VERSION 5.7 ;
  NOWIREEXTENSIONATPIN ON ;
  DIVIDERCHAR "/" ;
  BUSBITCHARS "[]" ;
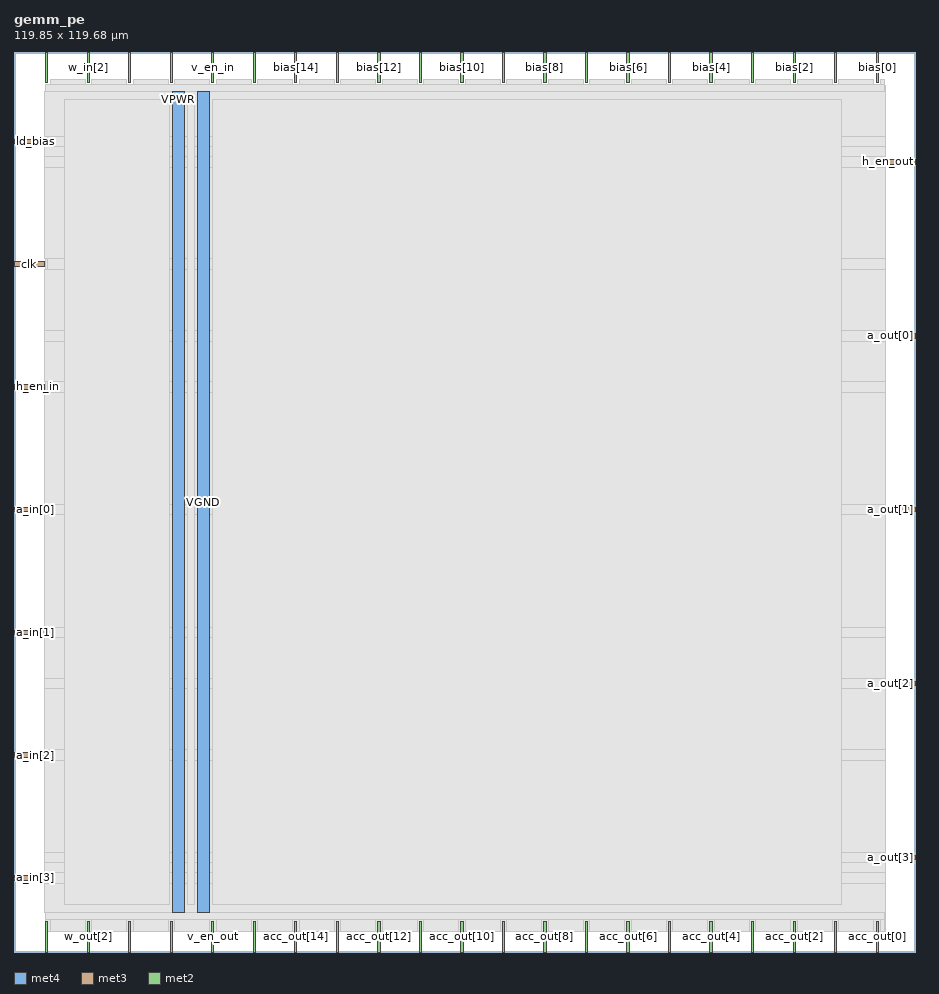
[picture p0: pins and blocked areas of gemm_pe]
MACRO gemm_pe
  CLASS BLOCK ;
  FOREIGN gemm_pe ;
  ORIGIN 0.000 0.000 ;
  SIZE 119.850 BY 119.680 ;
  PIN VGND
    DIRECTION INOUT ;
    USE GROUND ;
    PORT
      LAYER met4 ;
        RECT 24.340 5.200 25.940 114.480 ;
    END
  END VGND
  PIN VPWR
    DIRECTION INOUT ;
    USE POWER ;
    PORT
      LAYER met4 ;
        RECT 21.040 5.200 22.640 114.480 ;
    END
  END VPWR
  PIN a_in[0]
    DIRECTION INPUT ;
    USE SIGNAL ;
    ANTENNAGATEAREA 0.990000 ;
    PORT
      LAYER met3 ;
        RECT 0.000 58.520 4.000 59.120 ;
    END
  END a_in[0]
  PIN a_in[1]
    DIRECTION INPUT ;
    USE SIGNAL ;
    ANTENNAGATEAREA 1.237500 ;
    PORT
      LAYER met3 ;
        RECT 0.000 42.200 4.000 42.800 ;
    END
  END a_in[1]
  PIN a_in[2]
    DIRECTION INPUT ;
    USE SIGNAL ;
    ANTENNAGATEAREA 1.485000 ;
    PORT
      LAYER met3 ;
        RECT 0.000 25.880 4.000 26.480 ;
    END
  END a_in[2]
  PIN a_in[3]
    DIRECTION INPUT ;
    USE SIGNAL ;
    ANTENNAGATEAREA 1.116000 ;
    PORT
      LAYER met3 ;
        RECT 0.000 9.560 4.000 10.160 ;
    END
  END a_in[3]
  PIN a_out[0]
    DIRECTION OUTPUT ;
    USE SIGNAL ;
    ANTENNADIFFAREA 0.445500 ;
    PORT
      LAYER met3 ;
        RECT 115.850 81.640 119.850 82.240 ;
    END
  END a_out[0]
  PIN a_out[1]
    DIRECTION OUTPUT ;
    USE SIGNAL ;
    ANTENNADIFFAREA 0.445500 ;
    PORT
      LAYER met3 ;
        RECT 115.850 58.520 119.850 59.120 ;
    END
  END a_out[1]
  PIN a_out[2]
    DIRECTION OUTPUT ;
    USE SIGNAL ;
    ANTENNADIFFAREA 0.445500 ;
    PORT
      LAYER met3 ;
        RECT 115.850 35.400 119.850 36.000 ;
    END
  END a_out[2]
  PIN a_out[3]
    DIRECTION OUTPUT ;
    USE SIGNAL ;
    ANTENNADIFFAREA 0.445500 ;
    PORT
      LAYER met3 ;
        RECT 115.850 12.280 119.850 12.880 ;
    END
  END a_out[3]
  PIN acc_out[0]
    DIRECTION OUTPUT ;
    USE SIGNAL ;
    ANTENNAGATEAREA 2.475000 ;
    ANTENNADIFFAREA 0.445500 ;
    PORT
      LAYER met2 ;
        RECT 114.630 0.000 114.910 4.000 ;
    END
  END acc_out[0]
  PIN acc_out[10]
    DIRECTION OUTPUT ;
    USE SIGNAL ;
    ANTENNAGATEAREA 2.227500 ;
    ANTENNADIFFAREA 0.445500 ;
    PORT
      LAYER met2 ;
        RECT 59.430 0.000 59.710 4.000 ;
    END
  END acc_out[10]
  PIN acc_out[11]
    DIRECTION OUTPUT ;
    USE SIGNAL ;
    ANTENNAGATEAREA 2.722500 ;
    ANTENNADIFFAREA 0.445500 ;
    PORT
      LAYER met2 ;
        RECT 53.910 0.000 54.190 4.000 ;
    END
  END acc_out[11]
  PIN acc_out[12]
    DIRECTION OUTPUT ;
    USE SIGNAL ;
    ANTENNAGATEAREA 2.227500 ;
    ANTENNADIFFAREA 0.445500 ;
    PORT
      LAYER met2 ;
        RECT 48.390 0.000 48.670 4.000 ;
    END
  END acc_out[12]
  PIN acc_out[13]
    DIRECTION OUTPUT ;
    USE SIGNAL ;
    ANTENNAGATEAREA 2.227500 ;
    ANTENNADIFFAREA 0.445500 ;
    PORT
      LAYER met2 ;
        RECT 42.870 0.000 43.150 4.000 ;
    END
  END acc_out[13]
  PIN acc_out[14]
    DIRECTION OUTPUT ;
    USE SIGNAL ;
    ANTENNAGATEAREA 4.207500 ;
    ANTENNADIFFAREA 0.445500 ;
    PORT
      LAYER met2 ;
        RECT 37.350 0.000 37.630 4.000 ;
    END
  END acc_out[14]
  PIN acc_out[15]
    DIRECTION OUTPUT ;
    USE SIGNAL ;
    ANTENNADIFFAREA 0.445500 ;
    PORT
      LAYER met2 ;
        RECT 31.830 0.000 32.110 4.000 ;
    END
  END acc_out[15]
  PIN acc_out[1]
    DIRECTION OUTPUT ;
    USE SIGNAL ;
    ANTENNAGATEAREA 1.980000 ;
    ANTENNADIFFAREA 0.445500 ;
    PORT
      LAYER met2 ;
        RECT 109.110 0.000 109.390 4.000 ;
    END
  END acc_out[1]
  PIN acc_out[2]
    DIRECTION OUTPUT ;
    USE SIGNAL ;
    ANTENNAGATEAREA 1.485000 ;
    ANTENNADIFFAREA 0.445500 ;
    PORT
      LAYER met2 ;
        RECT 103.590 0.000 103.870 4.000 ;
    END
  END acc_out[2]
  PIN acc_out[3]
    DIRECTION OUTPUT ;
    USE SIGNAL ;
    ANTENNAGATEAREA 1.485000 ;
    ANTENNADIFFAREA 0.445500 ;
    PORT
      LAYER met2 ;
        RECT 98.070 0.000 98.350 4.000 ;
    END
  END acc_out[3]
  PIN acc_out[4]
    DIRECTION OUTPUT ;
    USE SIGNAL ;
    ANTENNAGATEAREA 1.980000 ;
    ANTENNADIFFAREA 0.445500 ;
    PORT
      LAYER met2 ;
        RECT 92.550 0.000 92.830 4.000 ;
    END
  END acc_out[4]
  PIN acc_out[5]
    DIRECTION OUTPUT ;
    USE SIGNAL ;
    ANTENNAGATEAREA 1.485000 ;
    ANTENNADIFFAREA 0.445500 ;
    PORT
      LAYER met2 ;
        RECT 87.030 0.000 87.310 4.000 ;
    END
  END acc_out[5]
  PIN acc_out[6]
    DIRECTION OUTPUT ;
    USE SIGNAL ;
    ANTENNAGATEAREA 1.485000 ;
    ANTENNADIFFAREA 0.445500 ;
    PORT
      LAYER met2 ;
        RECT 81.510 0.000 81.790 4.000 ;
    END
  END acc_out[6]
  PIN acc_out[7]
    DIRECTION OUTPUT ;
    USE SIGNAL ;
    ANTENNAGATEAREA 2.050500 ;
    ANTENNADIFFAREA 0.445500 ;
    PORT
      LAYER met2 ;
        RECT 75.990 0.000 76.270 4.000 ;
    END
  END acc_out[7]
  PIN acc_out[8]
    DIRECTION OUTPUT ;
    USE SIGNAL ;
    ANTENNAGATEAREA 1.681500 ;
    ANTENNADIFFAREA 0.445500 ;
    PORT
      LAYER met2 ;
        RECT 70.470 0.000 70.750 4.000 ;
    END
  END acc_out[8]
  PIN acc_out[9]
    DIRECTION OUTPUT ;
    USE SIGNAL ;
    ANTENNAGATEAREA 1.929000 ;
    ANTENNADIFFAREA 0.445500 ;
    PORT
      LAYER met2 ;
        RECT 64.950 0.000 65.230 4.000 ;
    END
  END acc_out[9]
  PIN bias[0]
    DIRECTION INPUT ;
    USE SIGNAL ;
    ANTENNAGATEAREA 0.159000 ;
    PORT
      LAYER met2 ;
        RECT 114.630 115.680 114.910 119.680 ;
    END
  END bias[0]
  PIN bias[10]
    DIRECTION INPUT ;
    USE SIGNAL ;
    ANTENNAGATEAREA 0.247500 ;
    PORT
      LAYER met2 ;
        RECT 59.430 115.680 59.710 119.680 ;
    END
  END bias[10]
  PIN bias[11]
    DIRECTION INPUT ;
    USE SIGNAL ;
    ANTENNAGATEAREA 0.247500 ;
    PORT
      LAYER met2 ;
        RECT 53.910 115.680 54.190 119.680 ;
    END
  END bias[11]
  PIN bias[12]
    DIRECTION INPUT ;
    USE SIGNAL ;
    ANTENNAGATEAREA 0.159000 ;
    PORT
      LAYER met2 ;
        RECT 48.390 115.680 48.670 119.680 ;
    END
  END bias[12]
  PIN bias[13]
    DIRECTION INPUT ;
    USE SIGNAL ;
    ANTENNAGATEAREA 0.159000 ;
    PORT
      LAYER met2 ;
        RECT 42.870 115.680 43.150 119.680 ;
    END
  END bias[13]
  PIN bias[14]
    DIRECTION INPUT ;
    USE SIGNAL ;
    ANTENNAGATEAREA 0.247500 ;
    PORT
      LAYER met2 ;
        RECT 37.350 115.680 37.630 119.680 ;
    END
  END bias[14]
  PIN bias[15]
    DIRECTION INPUT ;
    USE SIGNAL ;
    ANTENNAGATEAREA 0.495000 ;
    PORT
      LAYER met2 ;
        RECT 31.830 115.680 32.110 119.680 ;
    END
  END bias[15]
  PIN bias[1]
    DIRECTION INPUT ;
    USE SIGNAL ;
    ANTENNAGATEAREA 0.159000 ;
    PORT
      LAYER met2 ;
        RECT 109.110 115.680 109.390 119.680 ;
    END
  END bias[1]
  PIN bias[2]
    DIRECTION INPUT ;
    USE SIGNAL ;
    ANTENNAGATEAREA 0.159000 ;
    PORT
      LAYER met2 ;
        RECT 103.590 115.680 103.870 119.680 ;
    END
  END bias[2]
  PIN bias[3]
    DIRECTION INPUT ;
    USE SIGNAL ;
    ANTENNAGATEAREA 0.159000 ;
    PORT
      LAYER met2 ;
        RECT 98.070 115.680 98.350 119.680 ;
    END
  END bias[3]
  PIN bias[4]
    DIRECTION INPUT ;
    USE SIGNAL ;
    ANTENNAGATEAREA 0.159000 ;
    PORT
      LAYER met2 ;
        RECT 92.550 115.680 92.830 119.680 ;
    END
  END bias[4]
  PIN bias[5]
    DIRECTION INPUT ;
    USE SIGNAL ;
    ANTENNAGATEAREA 0.159000 ;
    PORT
      LAYER met2 ;
        RECT 87.030 115.680 87.310 119.680 ;
    END
  END bias[5]
  PIN bias[6]
    DIRECTION INPUT ;
    USE SIGNAL ;
    ANTENNAGATEAREA 0.593700 ;
    ANTENNADIFFAREA 0.434700 ;
    PORT
      LAYER met2 ;
        RECT 81.510 115.680 81.790 119.680 ;
    END
  END bias[6]
  PIN bias[7]
    DIRECTION INPUT ;
    USE SIGNAL ;
    ANTENNAGATEAREA 0.593700 ;
    ANTENNADIFFAREA 0.434700 ;
    PORT
      LAYER met2 ;
        RECT 75.990 115.680 76.270 119.680 ;
    END
  END bias[7]
  PIN bias[8]
    DIRECTION INPUT ;
    USE SIGNAL ;
    ANTENNAGATEAREA 0.593700 ;
    ANTENNADIFFAREA 0.434700 ;
    PORT
      LAYER met2 ;
        RECT 70.470 115.680 70.750 119.680 ;
    END
  END bias[8]
  PIN bias[9]
    DIRECTION INPUT ;
    USE SIGNAL ;
    ANTENNAGATEAREA 0.593700 ;
    ANTENNADIFFAREA 0.434700 ;
    PORT
      LAYER met2 ;
        RECT 64.950 115.680 65.230 119.680 ;
    END
  END bias[9]
  PIN clk
    DIRECTION INPUT ;
    USE SIGNAL ;
    ANTENNAGATEAREA 0.852000 ;
    PORT
      LAYER met3 ;
        RECT 0.000 91.160 4.000 91.760 ;
    END
  END clk
  PIN h_en_in
    DIRECTION INPUT ;
    USE SIGNAL ;
    ANTENNAGATEAREA 2.601000 ;
    PORT
      LAYER met3 ;
        RECT 0.000 74.840 4.000 75.440 ;
    END
  END h_en_in
  PIN h_en_out
    DIRECTION OUTPUT ;
    USE SIGNAL ;
    ANTENNADIFFAREA 0.445500 ;
    PORT
      LAYER met3 ;
        RECT 115.850 104.760 119.850 105.360 ;
    END
  END h_en_out
  PIN ld_bias
    DIRECTION INPUT ;
    USE SIGNAL ;
    ANTENNAGATEAREA 4.383000 ;
    PORT
      LAYER met3 ;
        RECT 0.000 107.480 4.000 108.080 ;
    END
  END ld_bias
  PIN v_en_in
    DIRECTION INPUT ;
    USE SIGNAL ;
    ANTENNAGATEAREA 2.601000 ;
    PORT
      LAYER met2 ;
        RECT 26.310 115.680 26.590 119.680 ;
    END
  END v_en_in
  PIN v_en_out
    DIRECTION OUTPUT ;
    USE SIGNAL ;
    ANTENNADIFFAREA 0.445500 ;
    PORT
      LAYER met2 ;
        RECT 26.310 0.000 26.590 4.000 ;
    END
  END v_en_out
  PIN w_in[0]
    DIRECTION INPUT ;
    USE SIGNAL ;
    ANTENNAGATEAREA 0.990000 ;
    PORT
      LAYER met2 ;
        RECT 20.790 115.680 21.070 119.680 ;
    END
  END w_in[0]
  PIN w_in[1]
    DIRECTION INPUT ;
    USE SIGNAL ;
    ANTENNAGATEAREA 1.237500 ;
    PORT
      LAYER met2 ;
        RECT 15.270 115.680 15.550 119.680 ;
    END
  END w_in[1]
  PIN w_in[2]
    DIRECTION INPUT ;
    USE SIGNAL ;
    ANTENNAGATEAREA 1.485000 ;
    PORT
      LAYER met2 ;
        RECT 9.750 115.680 10.030 119.680 ;
    END
  END w_in[2]
  PIN w_in[3]
    DIRECTION INPUT ;
    USE SIGNAL ;
    ANTENNAGATEAREA 1.116000 ;
    PORT
      LAYER met2 ;
        RECT 4.230 115.680 4.510 119.680 ;
    END
  END w_in[3]
  PIN w_out[0]
    DIRECTION OUTPUT ;
    USE SIGNAL ;
    ANTENNADIFFAREA 0.445500 ;
    PORT
      LAYER met2 ;
        RECT 20.790 0.000 21.070 4.000 ;
    END
  END w_out[0]
  PIN w_out[1]
    DIRECTION OUTPUT ;
    USE SIGNAL ;
    ANTENNADIFFAREA 0.445500 ;
    PORT
      LAYER met2 ;
        RECT 15.270 0.000 15.550 4.000 ;
    END
  END w_out[1]
  PIN w_out[2]
    DIRECTION OUTPUT ;
    USE SIGNAL ;
    ANTENNADIFFAREA 0.445500 ;
    PORT
      LAYER met2 ;
        RECT 9.750 0.000 10.030 4.000 ;
    END
  END w_out[2]
  PIN w_out[3]
    DIRECTION OUTPUT ;
    USE SIGNAL ;
    ANTENNADIFFAREA 0.445500 ;
    PORT
      LAYER met2 ;
        RECT 4.230 0.000 4.510 4.000 ;
    END
  END w_out[3]
  OBS
      LAYER nwell ;
        RECT 5.330 5.355 114.270 114.325 ;
      LAYER li1 ;
        RECT 5.520 5.355 114.080 114.325 ;
      LAYER met1 ;
        RECT 4.210 2.760 115.850 115.220 ;
      LAYER met2 ;
        RECT 4.790 115.400 9.470 116.010 ;
        RECT 10.310 115.400 14.990 116.010 ;
        RECT 15.830 115.400 20.510 116.010 ;
        RECT 21.350 115.400 26.030 116.010 ;
        RECT 26.870 115.400 31.550 116.010 ;
        RECT 32.390 115.400 37.070 116.010 ;
        RECT 37.910 115.400 42.590 116.010 ;
        RECT 43.430 115.400 48.110 116.010 ;
        RECT 48.950 115.400 53.630 116.010 ;
        RECT 54.470 115.400 59.150 116.010 ;
        RECT 59.990 115.400 64.670 116.010 ;
        RECT 65.510 115.400 70.190 116.010 ;
        RECT 71.030 115.400 75.710 116.010 ;
        RECT 76.550 115.400 81.230 116.010 ;
        RECT 82.070 115.400 86.750 116.010 ;
        RECT 87.590 115.400 92.270 116.010 ;
        RECT 93.110 115.400 97.790 116.010 ;
        RECT 98.630 115.400 103.310 116.010 ;
        RECT 104.150 115.400 108.830 116.010 ;
        RECT 109.670 115.400 114.350 116.010 ;
        RECT 115.190 115.400 115.820 116.010 ;
        RECT 4.240 4.280 115.820 115.400 ;
        RECT 4.790 2.730 9.470 4.280 ;
        RECT 10.310 2.730 14.990 4.280 ;
        RECT 15.830 2.730 20.510 4.280 ;
        RECT 21.350 2.730 26.030 4.280 ;
        RECT 26.870 2.730 31.550 4.280 ;
        RECT 32.390 2.730 37.070 4.280 ;
        RECT 37.910 2.730 42.590 4.280 ;
        RECT 43.430 2.730 48.110 4.280 ;
        RECT 48.950 2.730 53.630 4.280 ;
        RECT 54.470 2.730 59.150 4.280 ;
        RECT 59.990 2.730 64.670 4.280 ;
        RECT 65.510 2.730 70.190 4.280 ;
        RECT 71.030 2.730 75.710 4.280 ;
        RECT 76.550 2.730 81.230 4.280 ;
        RECT 82.070 2.730 86.750 4.280 ;
        RECT 87.590 2.730 92.270 4.280 ;
        RECT 93.110 2.730 97.790 4.280 ;
        RECT 98.630 2.730 103.310 4.280 ;
        RECT 104.150 2.730 108.830 4.280 ;
        RECT 109.670 2.730 114.350 4.280 ;
        RECT 115.190 2.730 115.820 4.280 ;
      LAYER met3 ;
        RECT 4.000 108.480 115.850 114.405 ;
        RECT 4.400 107.080 115.850 108.480 ;
        RECT 4.000 105.760 115.850 107.080 ;
        RECT 4.000 104.360 115.450 105.760 ;
        RECT 4.000 92.160 115.850 104.360 ;
        RECT 4.400 90.760 115.850 92.160 ;
        RECT 4.000 82.640 115.850 90.760 ;
        RECT 4.000 81.240 115.450 82.640 ;
        RECT 4.000 75.840 115.850 81.240 ;
        RECT 4.400 74.440 115.850 75.840 ;
        RECT 4.000 59.520 115.850 74.440 ;
        RECT 4.400 58.120 115.450 59.520 ;
        RECT 4.000 43.200 115.850 58.120 ;
        RECT 4.400 41.800 115.850 43.200 ;
        RECT 4.000 36.400 115.850 41.800 ;
        RECT 4.000 35.000 115.450 36.400 ;
        RECT 4.000 26.880 115.850 35.000 ;
        RECT 4.400 25.480 115.850 26.880 ;
        RECT 4.000 13.280 115.850 25.480 ;
        RECT 4.000 11.880 115.450 13.280 ;
        RECT 4.000 10.560 115.850 11.880 ;
        RECT 4.400 9.160 115.850 10.560 ;
        RECT 4.000 5.275 115.850 9.160 ;
      LAYER met4 ;
        RECT 6.735 6.295 20.640 113.385 ;
        RECT 23.040 6.295 23.940 113.385 ;
        RECT 26.340 6.295 110.105 113.385 ;
  END
END gemm_pe
END LIBRARY

